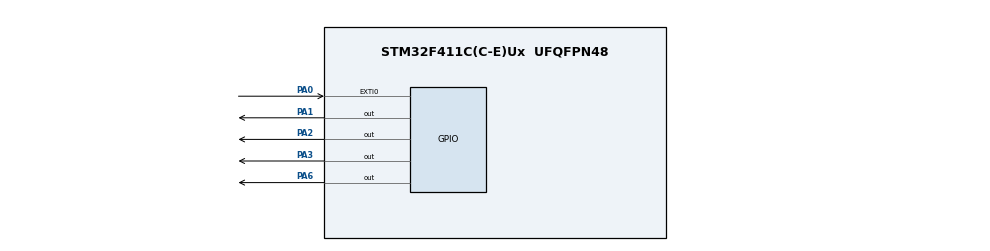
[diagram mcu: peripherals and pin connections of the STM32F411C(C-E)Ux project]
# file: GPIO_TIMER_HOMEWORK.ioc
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Mcu.Family=STM32F4
Mcu.Name=STM32F411C(C-E)Ux
Mcu.Package=UFQFPN48
NVIC.EXTI0_IRQn=true\:0\:0\:false\:false\:true\:true\:true\:true
NVIC.PriorityGroup=NVIC_PRIORITYGROUP_4
PA0-WKUP.Signal=GPXTI0
PA1.Signal=GPIO_Output
PA13.Mode=Serial_Wire
PA13.Signal=SYS_JTMS-SWDIO
PA14.Mode=Serial_Wire
PA14.Signal=SYS_JTCK-SWCLK
PA2.Signal=GPIO_Output
PA3.Signal=GPIO_Output
PA6.Signal=GPIO_Output
PB10.Signal=S_TIM2_CH3
PH0\ -\ OSC_IN.Mode=HSE-External-Oscillator
PH0\ -\ OSC_IN.Signal=RCC_OSC_IN
PH1\ -\ OSC_OUT.Mode=HSE-External-Oscillator
PH1\ -\ OSC_OUT.Signal=RCC_OSC_OUT
ProjectManager.HeapSize=0x200
ProjectManager.StackSize=0x400
ProjectManager.TargetToolchain=STM32CubeIDE
RCC.48MHZClocksFreq_Value=36000000
RCC.AHBFreq_Value=72000000
RCC.APB1CLKDivider=RCC_HCLK_DIV2
RCC.APB1Freq_Value=36000000
RCC.APB1TimFreq_Value=72000000
RCC.APB2Freq_Value=72000000
RCC.APB2TimFreq_Value=72000000
RCC.CortexFreq_Value=72000000
RCC.HCLKFreq_Value=72000000
RCC.HSE_VALUE=25000000
RCC.HSI_VALUE=16000000
RCC.LSE_VALUE=32768
RCC.PLLM=25
RCC.PLLN=144
RCC.PLLSourceVirtual=RCC_PLLSOURCE_HSE
RCC.SYSCLKFreq_VALUE=72000000
RCC.SYSCLKSource=RCC_SYSCLKSOURCE_PLLCLK
RCC.VCOOutputFreq_Value=144000000
SH.S_TIM2_CH3.0=TIM2_CH3
TIM2.AutoReloadPreload=TIM_AUTORELOAD_PRELOAD_DISABLE
TIM2.Prescaler=71
VP_TIM2_VS_ClockSourceINT.Mode=Internal
board=custom

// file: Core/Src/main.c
/* USER CODE BEGIN Header */
/**
  ******************************************************************************
  * @file           : main.c
  * @brief          : Main program body
  ******************************************************************************
  * @attention
  *
  * Copyright (c) 2025 STMicroelectronics.
  * All rights reserved.
  *
  * This software is licensed under terms that can be found in the LICENSE file
  * in the root directory of this software component.
  * If no LICENSE file comes with this software, it is provided AS-IS.
  *
  ******************************************************************************
  */
/* USER CODE END Header */
#include "main.h"

/* USER CODE BEGIN Includes */
unsigned int count;
/* USER CODE END Includes */

TIM_HandleTypeDef htim2;

/* USER CODE BEGIN PV */
void GPIOB_Config(void) {
	RCC ->AHB1ENR |= (0x01 << 1) ;
    GPIOB -> MODER &= ~(0x03 << (1*2)) ;
	GPIOB -> PUPDR |= (0x01 << (1*2)) ;
}

unsigned char Read_PB1 (void) {
	return (GPIOB -> IDR & (1 << 1)) ? 1 :0;
}

void HAL_GPIO_EXTI_Callback(uint16_t GPIO_Pin) {
   count++;
}
/* USER CODE END PV */

void SystemClock_Config(void);
static void MX_GPIO_Init(void);
static void MX_TIM2_Init(void);

int main(void)
{

  /* MCU Configuration--------------------------------------------------------*/

  /* Reset of all peripherals, Initializes the Flash interface and the Systick. */
  HAL_Init();

  /* Configure the system clock */
  SystemClock_Config();

  /* Initialize all configured peripherals */
  MX_GPIO_Init();
  MX_TIM2_Init();

  /* Infinite loop */
  /* USER CODE BEGIN WHILE */
  while (1)
  {
	  if (Read_PB1()) {
	  HAL_GPIO_TogglePin(GPIOC, GPIO_PIN_13);
	  HAL_Delay(250);
	  }
    /* USER CODE END WHILE */

  }
}

void SystemClock_Config(void)
{
  RCC_OscInitTypeDef RCC_OscInitStruct = {0};
  RCC_ClkInitTypeDef RCC_ClkInitStruct = {0};

  /** Configure the main internal regulator output voltage
  */
  HAL_PWREx_ControlVoltageScaling(PWR_REGULATOR_VOLTAGE_SCALE2);

  /** Initializes the RCC Oscillators according to the specified parameters
  * in the RCC_OscInitTypeDef structure.
  */
  RCC_OscInitStruct.OscillatorType = RCC_OSCILLATORTYPE_HSE;
  RCC_OscInitStruct.HSEState = RCC_HSE_ON;
  RCC_OscInitStruct.PLL.PLLState = RCC_PLL_ON;
  RCC_OscInitStruct.PLL.PLLSource = RCC_PLLSOURCE_HSE;
  RCC_OscInitStruct.PLL.PLLM = 8;
  RCC_OscInitStruct.PLL.PLLN = 96;
  RCC_OscInitStruct.PLL.PLLP = RCC_PLLP_DIV2;
  RCC_OscInitStruct.PLL.PLLQ = 4;
  if (HAL_RCC_OscConfig(&RCC_OscInitStruct) != HAL_OK)
  {
    Error_Handler();
  }

  /** Initializes the CPU, AHB and APB buses clocks
  */
  RCC_ClkInitStruct.ClockType = RCC_CLOCKTYPE_HCLK|RCC_CLOCKTYPE_SYSCLK
                              |RCC_CLOCKTYPE_PCLK1|RCC_CLOCKTYPE_PCLK2;
  RCC_ClkInitStruct.SYSCLKSource = RCC_SYSCLKSOURCE_PLLCLK;
  RCC_ClkInitStruct.AHBCLKDivider = RCC_SYSCLK_DIV1;
  RCC_ClkInitStruct.APB1CLKDivider = RCC_HCLK_DIV2;
  RCC_ClkInitStruct.APB2CLKDivider = RCC_HCLK_DIV1;

  if (HAL_RCC_ClockConfig(&RCC_ClkInitStruct, FLASH_LATENCY_2) != HAL_OK)
  {
    Error_Handler();
  }
}

static void MX_TIM2_Init(void)
{

  TIM_ClockConfigTypeDef sClockSourceConfig = {0};
  TIM_MasterConfigTypeDef sMasterConfig = {0};

  htim2.Instance = TIM2;
  htim2.Init.Prescaler = 71;
  htim2.Init.CounterMode = TIM_COUNTERMODE_UP;
  htim2.Init.Period = 666666;
  htim2.Init.ClockDivision = TIM_CLOCKDIVISION_DIV1;
  htim2.Init.AutoReloadPreload = TIM_AUTORELOAD_PRELOAD_DISABLE;
  if (HAL_TIM_Base_Init(&htim2) != HAL_OK)
  {
    Error_Handler();
  }
  sClockSourceConfig.ClockSource = TIM_CLOCKSOURCE_INTERNAL;
  if (HAL_TIM_ConfigClockSource(&htim2, &sClockSourceConfig) != HAL_OK)
  {
    Error_Handler();
  }
  sMasterConfig.MasterOutputTrigger = TIM_TRGO_RESET;
  sMasterConfig.MasterSlaveMode = TIM_MASTERSLAVEMODE_DISABLE;
  if (HAL_TIMEx_MasterConfigSynchronization(&htim2, &sMasterConfig) != HAL_OK)
  {
    Error_Handler();
  }

}

static void MX_GPIO_Init(void) {
  GPIO_InitTypeDef GPIO_InitStruct = {0};

  /* GPIO Ports Clock Enable */
  __HAL_RCC_GPIOH_CLK_ENABLE();
  __HAL_RCC_GPIOA_CLK_ENABLE();
  __HAL_RCC_GPIOB_CLK_ENABLE();

  /*Configure GPIO pin Output Level */
  HAL_GPIO_WritePin(GPIOA, GPIO_PIN_1|GPIO_PIN_2|GPIO_PIN_3|GPIO_PIN_6, GPIO_PIN_RESET);

  /*Configure GPIO pin : PA0 */
  GPIO_InitStruct.Pin = GPIO_PIN_0;
  GPIO_InitStruct.Mode = GPIO_MODE_IT_RISING;
  GPIO_InitStruct.Pull = GPIO_NOPULL;
  HAL_GPIO_Init(GPIOA, &GPIO_InitStruct);

  /*Configure GPIO pins : PA1 PA2 PA3 PA6 */
  GPIO_InitStruct.Pin = GPIO_PIN_1|GPIO_PIN_2|GPIO_PIN_3|GPIO_PIN_6;
  GPIO_InitStruct.Mode = GPIO_MODE_OUTPUT_PP;
  GPIO_InitStruct.Pull = GPIO_NOPULL;
  GPIO_InitStruct.Speed = GPIO_SPEED_FREQ_LOW;
  HAL_GPIO_Init(GPIOA, &GPIO_InitStruct);

  /* EXTI interrupt init*/
  HAL_NVIC_SetPriority(EXTI0_IRQn, 0, 0);
  HAL_NVIC_EnableIRQ(EXTI0_IRQn);

  /* USER CODE BEGIN MX_GPIO_Init_2 */
  HAL_NVIC_SetPriority(EXTI1_IRQn, 0, 0);
  HAL_NVIC_EnableIRQ(EXTI1_IRQn);
  /* USER CODE END MX_GPIO_Init_2 */
}

void Error_Handler(void)
{
  __disable_irq();
  while (1)
  {
  }
}
